VERSION 5.7 ;
  NOWIREEXTENSIONATPIN ON ;
  DIVIDERCHAR "/" ;
  BUSBITCHARS "[]" ;
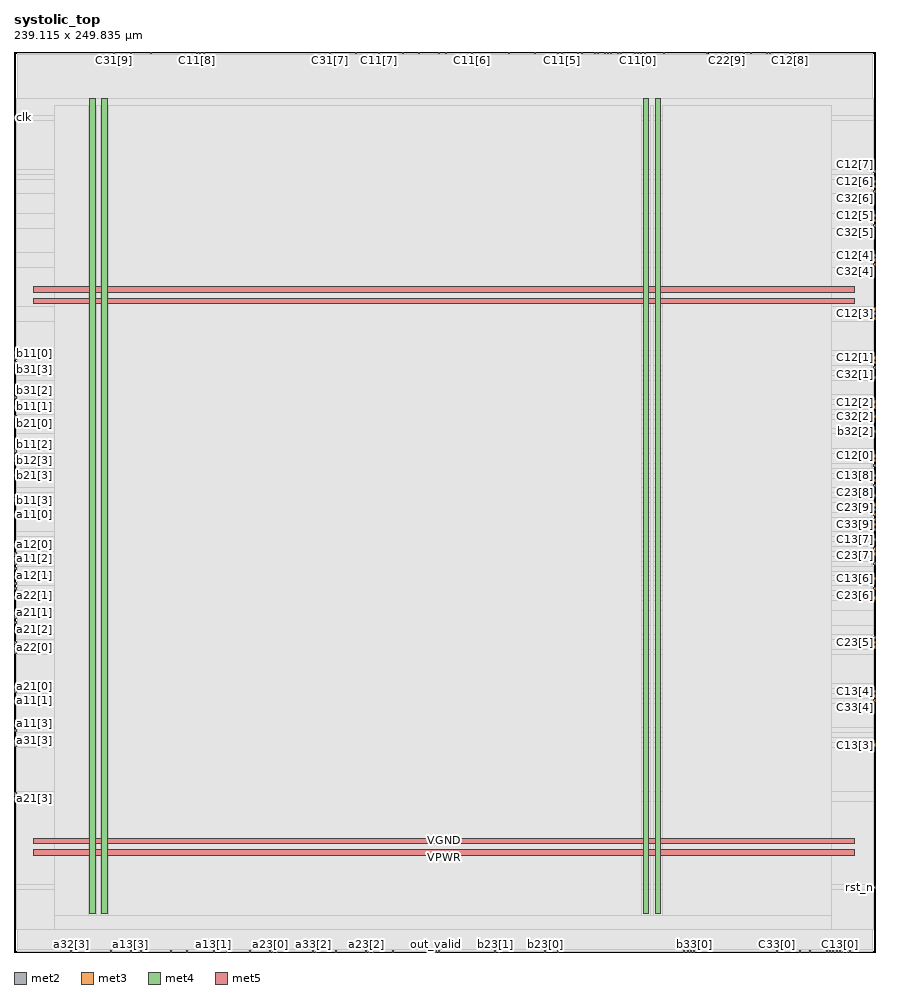
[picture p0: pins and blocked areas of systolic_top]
MACRO systolic_top
  CLASS BLOCK ;
  FOREIGN systolic_top ;
  ORIGIN 0.000 0.000 ;
  SIZE 239.115 BY 249.835 ;
  PIN C11[0]
    DIRECTION OUTPUT ;
    USE SIGNAL ;
    ANTENNADIFFAREA 0.702900 ;
    PORT
      LAYER met2 ;
        RECT 173.050 249.555 173.330 249.835 ;
    END
  END C11[0]
  PIN C11[1]
    DIRECTION OUTPUT ;
    USE SIGNAL ;
    ANTENNADIFFAREA 0.702900 ;
    PORT
      LAYER met2 ;
        RECT 165.690 249.555 165.970 249.835 ;
    END
  END C11[1]
  PIN C11[2]
    DIRECTION OUTPUT ;
    USE SIGNAL ;
    ANTENNADIFFAREA 0.702900 ;
    PORT
      LAYER met2 ;
        RECT 174.890 249.555 175.170 249.835 ;
    END
  END C11[2]
  PIN C11[3]
    DIRECTION OUTPUT ;
    USE SIGNAL ;
    ANTENNADIFFAREA 0.702900 ;
    PORT
      LAYER met2 ;
        RECT 180.410 249.555 180.690 249.835 ;
    END
  END C11[3]
  PIN C11[4]
    DIRECTION OUTPUT ;
    USE SIGNAL ;
    ANTENNADIFFAREA 0.702900 ;
    PORT
      LAYER met2 ;
        RECT 172.130 249.555 172.410 249.835 ;
    END
  END C11[4]
  PIN C11[5]
    DIRECTION OUTPUT ;
    USE SIGNAL ;
    ANTENNADIFFAREA 0.702900 ;
    PORT
      LAYER met2 ;
        RECT 151.890 249.555 152.170 249.835 ;
    END
  END C11[5]
  PIN C11[6]
    DIRECTION OUTPUT ;
    USE SIGNAL ;
    ANTENNADIFFAREA 0.702900 ;
    PORT
      LAYER met2 ;
        RECT 127.050 249.555 127.330 249.835 ;
    END
  END C11[6]
  PIN C11[7]
    DIRECTION OUTPUT ;
    USE SIGNAL ;
    ANTENNADIFFAREA 0.702900 ;
    PORT
      LAYER met2 ;
        RECT 101.290 249.555 101.570 249.835 ;
    END
  END C11[7]
  PIN C11[8]
    DIRECTION OUTPUT ;
    USE SIGNAL ;
    ANTENNADIFFAREA 0.702900 ;
    PORT
      LAYER met2 ;
        RECT 50.690 249.555 50.970 249.835 ;
    END
  END C11[8]
  PIN C11[9]
    DIRECTION OUTPUT ;
    USE SIGNAL ;
    ANTENNADIFFAREA 0.702900 ;
    PORT
      LAYER met2 ;
        RECT 37.810 249.555 38.090 249.835 ;
    END
  END C11[9]
  PIN C12[0]
    DIRECTION OUTPUT ;
    USE SIGNAL ;
    ANTENNADIFFAREA 0.702900 ;
    PORT
      LAYER met3 ;
        RECT 238.515 137.400 239.115 138.000 ;
    END
  END C12[0]
  PIN C12[1]
    DIRECTION OUTPUT ;
    USE SIGNAL ;
    ANTENNADIFFAREA 0.702900 ;
    PORT
      LAYER met3 ;
        RECT 238.515 164.600 239.115 165.200 ;
    END
  END C12[1]
  PIN C12[2]
    DIRECTION OUTPUT ;
    USE SIGNAL ;
    ANTENNADIFFAREA 0.702900 ;
    PORT
      LAYER met3 ;
        RECT 238.515 152.360 239.115 152.960 ;
    END
  END C12[2]
  PIN C12[3]
    DIRECTION OUTPUT ;
    USE SIGNAL ;
    ANTENNADIFFAREA 0.702900 ;
    PORT
      LAYER met3 ;
        RECT 238.515 176.840 239.115 177.440 ;
    END
  END C12[3]
  PIN C12[4]
    DIRECTION OUTPUT ;
    USE SIGNAL ;
    ANTENNADIFFAREA 0.702900 ;
    PORT
      LAYER met3 ;
        RECT 238.515 193.160 239.115 193.760 ;
    END
  END C12[4]
  PIN C12[5]
    DIRECTION OUTPUT ;
    USE SIGNAL ;
    ANTENNADIFFAREA 0.702900 ;
    PORT
      LAYER met3 ;
        RECT 238.515 204.040 239.115 204.640 ;
    END
  END C12[5]
  PIN C12[6]
    DIRECTION OUTPUT ;
    USE SIGNAL ;
    ANTENNADIFFAREA 0.702900 ;
    PORT
      LAYER met3 ;
        RECT 238.515 213.560 239.115 214.160 ;
    END
  END C12[6]
  PIN C12[7]
    DIRECTION OUTPUT ;
    USE SIGNAL ;
    ANTENNADIFFAREA 0.702900 ;
    PORT
      LAYER met3 ;
        RECT 238.515 216.280 239.115 216.880 ;
    END
  END C12[7]
  PIN C12[8]
    DIRECTION OUTPUT ;
    USE SIGNAL ;
    ANTENNADIFFAREA 0.702900 ;
    PORT
      LAYER met2 ;
        RECT 215.370 249.555 215.650 249.835 ;
    END
  END C12[8]
  PIN C12[9]
    DIRECTION OUTPUT ;
    USE SIGNAL ;
    ANTENNADIFFAREA 0.702900 ;
    PORT
      LAYER met2 ;
        RECT 204.330 249.555 204.610 249.835 ;
    END
  END C12[9]
  PIN C13[0]
    DIRECTION OUTPUT ;
    USE SIGNAL ;
    ANTENNADIFFAREA 0.702900 ;
    PORT
      LAYER met2 ;
        RECT 229.170 0.000 229.450 0.280 ;
    END
  END C13[0]
  PIN C13[1]
    DIRECTION OUTPUT ;
    USE SIGNAL ;
    ANTENNADIFFAREA 0.702900 ;
    PORT
      LAYER met2 ;
        RECT 231.930 0.000 232.210 0.280 ;
    END
  END C13[1]
  PIN C13[2]
    DIRECTION OUTPUT ;
    USE SIGNAL ;
    ANTENNADIFFAREA 0.702900 ;
    PORT
      LAYER met2 ;
        RECT 231.010 0.000 231.290 0.280 ;
    END
  END C13[2]
  PIN C13[3]
    DIRECTION OUTPUT ;
    USE SIGNAL ;
    ANTENNADIFFAREA 0.702900 ;
    PORT
      LAYER met3 ;
        RECT 238.515 57.160 239.115 57.760 ;
    END
  END C13[3]
  PIN C13[4]
    DIRECTION OUTPUT ;
    USE SIGNAL ;
    ANTENNADIFFAREA 0.702900 ;
    PORT
      LAYER met3 ;
        RECT 238.515 72.120 239.115 72.720 ;
    END
  END C13[4]
  PIN C13[5]
    DIRECTION OUTPUT ;
    USE SIGNAL ;
    ANTENNADIFFAREA 0.702900 ;
    PORT
      LAYER met3 ;
        RECT 238.515 87.080 239.115 87.680 ;
    END
  END C13[5]
  PIN C13[6]
    DIRECTION OUTPUT ;
    USE SIGNAL ;
    ANTENNADIFFAREA 0.702900 ;
    PORT
      LAYER met3 ;
        RECT 238.515 103.400 239.115 104.000 ;
    END
  END C13[6]
  PIN C13[7]
    DIRECTION OUTPUT ;
    USE SIGNAL ;
    ANTENNADIFFAREA 0.702900 ;
    PORT
      LAYER met3 ;
        RECT 238.515 114.280 239.115 114.880 ;
    END
  END C13[7]
  PIN C13[8]
    DIRECTION OUTPUT ;
    USE SIGNAL ;
    ANTENNADIFFAREA 0.702900 ;
    PORT
      LAYER met3 ;
        RECT 238.515 131.960 239.115 132.560 ;
    END
  END C13[8]
  PIN C13[9]
    DIRECTION OUTPUT ;
    USE SIGNAL ;
    ANTENNADIFFAREA 0.702900 ;
    PORT
      LAYER met3 ;
        RECT 238.515 123.800 239.115 124.400 ;
    END
  END C13[9]
  PIN C21[0]
    DIRECTION OUTPUT ;
    USE SIGNAL ;
    ANTENNADIFFAREA 0.702900 ;
    PORT
      LAYER met2 ;
        RECT 167.530 249.555 167.810 249.835 ;
    END
  END C21[0]
  PIN C21[1]
    DIRECTION OUTPUT ;
    USE SIGNAL ;
    ANTENNADIFFAREA 0.702900 ;
    PORT
      LAYER met2 ;
        RECT 157.410 249.555 157.690 249.835 ;
    END
  END C21[1]
  PIN C21[2]
    DIRECTION OUTPUT ;
    USE SIGNAL ;
    ANTENNADIFFAREA 0.702900 ;
    PORT
      LAYER met2 ;
        RECT 168.450 249.555 168.730 249.835 ;
    END
  END C21[2]
  PIN C21[3]
    DIRECTION OUTPUT ;
    USE SIGNAL ;
    ANTENNADIFFAREA 0.702900 ;
    PORT
      LAYER met2 ;
        RECT 173.970 249.555 174.250 249.835 ;
    END
  END C21[3]
  PIN C21[4]
    DIRECTION OUTPUT ;
    USE SIGNAL ;
    ANTENNADIFFAREA 0.702900 ;
    PORT
      LAYER met2 ;
        RECT 164.770 249.555 165.050 249.835 ;
    END
  END C21[4]
  PIN C21[5]
    DIRECTION OUTPUT ;
    USE SIGNAL ;
    ANTENNADIFFAREA 0.702900 ;
    PORT
      LAYER met2 ;
        RECT 144.530 249.555 144.810 249.835 ;
    END
  END C21[5]
  PIN C21[6]
    DIRECTION OUTPUT ;
    USE SIGNAL ;
    ANTENNADIFFAREA 0.702900 ;
    PORT
      LAYER met2 ;
        RECT 119.690 249.555 119.970 249.835 ;
    END
  END C21[6]
  PIN C21[7]
    DIRECTION OUTPUT ;
    USE SIGNAL ;
    ANTENNADIFFAREA 0.702900 ;
    PORT
      LAYER met2 ;
        RECT 94.850 249.555 95.130 249.835 ;
    END
  END C21[7]
  PIN C21[8]
    DIRECTION OUTPUT ;
    USE SIGNAL ;
    ANTENNADIFFAREA 0.702900 ;
    PORT
      LAYER met2 ;
        RECT 51.610 249.555 51.890 249.835 ;
    END
  END C21[8]
  PIN C21[9]
    DIRECTION OUTPUT ;
    USE SIGNAL ;
    ANTENNADIFFAREA 0.702900 ;
    PORT
      LAYER met2 ;
        RECT 32.290 249.555 32.570 249.835 ;
    END
  END C21[9]
  PIN C22[0]
    DIRECTION OUTPUT ;
    USE SIGNAL ;
    ANTENNADIFFAREA 0.702900 ;
    PORT
      LAYER met3 ;
        RECT 238.515 134.680 239.115 135.280 ;
    END
  END C22[0]
  PIN C22[1]
    DIRECTION OUTPUT ;
    USE SIGNAL ;
    ANTENNADIFFAREA 0.702900 ;
    PORT
      LAYER met3 ;
        RECT 238.515 163.240 239.115 163.840 ;
    END
  END C22[1]
  PIN C22[2]
    DIRECTION OUTPUT ;
    USE SIGNAL ;
    ANTENNADIFFAREA 0.702900 ;
    PORT
      LAYER met3 ;
        RECT 238.515 151.000 239.115 151.600 ;
    END
  END C22[2]
  PIN C22[3]
    DIRECTION OUTPUT ;
    USE SIGNAL ;
    ANTENNADIFFAREA 0.702900 ;
    PORT
      LAYER met3 ;
        RECT 238.515 175.480 239.115 176.080 ;
    END
  END C22[3]
  PIN C22[4]
    DIRECTION OUTPUT ;
    USE SIGNAL ;
    ANTENNADIFFAREA 0.702900 ;
    PORT
      LAYER met3 ;
        RECT 238.515 191.800 239.115 192.400 ;
    END
  END C22[4]
  PIN C22[5]
    DIRECTION OUTPUT ;
    USE SIGNAL ;
    ANTENNADIFFAREA 0.702900 ;
    PORT
      LAYER met3 ;
        RECT 238.515 202.680 239.115 203.280 ;
    END
  END C22[5]
  PIN C22[6]
    DIRECTION OUTPUT ;
    USE SIGNAL ;
    ANTENNADIFFAREA 0.702900 ;
    PORT
      LAYER met3 ;
        RECT 238.515 212.200 239.115 212.800 ;
    END
  END C22[6]
  PIN C22[7]
    DIRECTION OUTPUT ;
    USE SIGNAL ;
    ANTENNADIFFAREA 0.702900 ;
    PORT
      LAYER met2 ;
        RECT 216.290 249.555 216.570 249.835 ;
    END
  END C22[7]
  PIN C22[8]
    DIRECTION OUTPUT ;
    USE SIGNAL ;
    ANTENNADIFFAREA 0.702900 ;
    PORT
      LAYER met2 ;
        RECT 208.930 249.555 209.210 249.835 ;
    END
  END C22[8]
  PIN C22[9]
    DIRECTION OUTPUT ;
    USE SIGNAL ;
    ANTENNADIFFAREA 0.702900 ;
    PORT
      LAYER met2 ;
        RECT 197.890 249.555 198.170 249.835 ;
    END
  END C22[9]
  PIN C23[0]
    DIRECTION OUTPUT ;
    USE SIGNAL ;
    ANTENNADIFFAREA 0.702900 ;
    PORT
      LAYER met2 ;
        RECT 220.890 0.000 221.170 0.280 ;
    END
  END C23[0]
  PIN C23[1]
    DIRECTION OUTPUT ;
    USE SIGNAL ;
    ANTENNADIFFAREA 0.702900 ;
    PORT
      LAYER met2 ;
        RECT 225.490 0.000 225.770 0.280 ;
    END
  END C23[1]
  PIN C23[2]
    DIRECTION OUTPUT ;
    USE SIGNAL ;
    ANTENNADIFFAREA 0.702900 ;
    PORT
      LAYER met2 ;
        RECT 228.250 0.000 228.530 0.280 ;
    END
  END C23[2]
  PIN C23[3]
    DIRECTION OUTPUT ;
    USE SIGNAL ;
    ANTENNADIFFAREA 0.702900 ;
    PORT
      LAYER met2 ;
        RECT 230.090 0.000 230.370 0.280 ;
    END
  END C23[3]
  PIN C23[4]
    DIRECTION OUTPUT ;
    USE SIGNAL ;
    ANTENNADIFFAREA 0.702900 ;
    PORT
      LAYER met3 ;
        RECT 238.515 70.760 239.115 71.360 ;
    END
  END C23[4]
  PIN C23[5]
    DIRECTION OUTPUT ;
    USE SIGNAL ;
    ANTENNADIFFAREA 0.702900 ;
    PORT
      LAYER met3 ;
        RECT 238.515 85.720 239.115 86.320 ;
    END
  END C23[5]
  PIN C23[6]
    DIRECTION OUTPUT ;
    USE SIGNAL ;
    ANTENNADIFFAREA 0.702900 ;
    PORT
      LAYER met3 ;
        RECT 238.515 100.680 239.115 101.280 ;
    END
  END C23[6]
  PIN C23[7]
    DIRECTION OUTPUT ;
    USE SIGNAL ;
    ANTENNADIFFAREA 0.702900 ;
    PORT
      LAYER met3 ;
        RECT 238.515 111.560 239.115 112.160 ;
    END
  END C23[7]
  PIN C23[8]
    DIRECTION OUTPUT ;
    USE SIGNAL ;
    ANTENNADIFFAREA 0.702900 ;
    PORT
      LAYER met3 ;
        RECT 238.515 129.240 239.115 129.840 ;
    END
  END C23[8]
  PIN C23[9]
    DIRECTION OUTPUT ;
    USE SIGNAL ;
    ANTENNADIFFAREA 0.702900 ;
    PORT
      LAYER met3 ;
        RECT 238.515 121.080 239.115 121.680 ;
    END
  END C23[9]
  PIN C31[0]
    DIRECTION OUTPUT ;
    USE SIGNAL ;
    ANTENNADIFFAREA 0.702900 ;
    PORT
      LAYER met2 ;
        RECT 161.090 249.555 161.370 249.835 ;
    END
  END C31[0]
  PIN C31[1]
    DIRECTION OUTPUT ;
    USE SIGNAL ;
    ANTENNADIFFAREA 0.702900 ;
    PORT
      LAYER met2 ;
        RECT 150.970 249.555 151.250 249.835 ;
    END
  END C31[1]
  PIN C31[2]
    DIRECTION OUTPUT ;
    USE SIGNAL ;
    ANTENNADIFFAREA 0.702900 ;
    PORT
      LAYER met2 ;
        RECT 162.010 249.555 162.290 249.835 ;
    END
  END C31[2]
  PIN C31[3]
    DIRECTION OUTPUT ;
    USE SIGNAL ;
    ANTENNADIFFAREA 0.702900 ;
    PORT
      LAYER met2 ;
        RECT 163.850 249.555 164.130 249.835 ;
    END
  END C31[3]
  PIN C31[4]
    DIRECTION OUTPUT ;
    USE SIGNAL ;
    ANTENNADIFFAREA 0.702900 ;
    PORT
      LAYER met2 ;
        RECT 156.490 249.555 156.770 249.835 ;
    END
  END C31[4]
  PIN C31[5]
    DIRECTION OUTPUT ;
    USE SIGNAL ;
    ANTENNADIFFAREA 0.702900 ;
    PORT
      LAYER met2 ;
        RECT 137.170 249.555 137.450 249.835 ;
    END
  END C31[5]
  PIN C31[6]
    DIRECTION OUTPUT ;
    USE SIGNAL ;
    ANTENNADIFFAREA 0.702900 ;
    PORT
      LAYER met2 ;
        RECT 112.330 249.555 112.610 249.835 ;
    END
  END C31[6]
  PIN C31[7]
    DIRECTION OUTPUT ;
    USE SIGNAL ;
    ANTENNADIFFAREA 0.702900 ;
    PORT
      LAYER met2 ;
        RECT 87.490 249.555 87.770 249.835 ;
    END
  END C31[7]
  PIN C31[8]
    DIRECTION OUTPUT ;
    USE SIGNAL ;
    ANTENNADIFFAREA 0.702900 ;
    PORT
      LAYER met2 ;
        RECT 52.530 249.555 52.810 249.835 ;
    END
  END C31[8]
  PIN C31[9]
    DIRECTION OUTPUT ;
    USE SIGNAL ;
    ANTENNADIFFAREA 0.702900 ;
    PORT
      LAYER met2 ;
        RECT 27.690 249.555 27.970 249.835 ;
    END
  END C31[9]
  PIN C32[0]
    DIRECTION OUTPUT ;
    USE SIGNAL ;
    ANTENNADIFFAREA 0.702900 ;
    PORT
      LAYER met3 ;
        RECT 238.515 136.040 239.115 136.640 ;
    END
  END C32[0]
  PIN C32[1]
    DIRECTION OUTPUT ;
    USE SIGNAL ;
    ANTENNADIFFAREA 0.702900 ;
    PORT
      LAYER met3 ;
        RECT 238.515 161.880 239.115 162.480 ;
    END
  END C32[1]
  PIN C32[2]
    DIRECTION OUTPUT ;
    USE SIGNAL ;
    ANTENNADIFFAREA 0.702900 ;
    PORT
      LAYER met3 ;
        RECT 238.515 148.280 239.115 148.880 ;
    END
  END C32[2]
  PIN C32[3]
    DIRECTION OUTPUT ;
    USE SIGNAL ;
    ANTENNADIFFAREA 0.702900 ;
    PORT
      LAYER met3 ;
        RECT 238.515 178.200 239.115 178.800 ;
    END
  END C32[3]
  PIN C32[4]
    DIRECTION OUTPUT ;
    USE SIGNAL ;
    ANTENNADIFFAREA 0.702900 ;
    PORT
      LAYER met3 ;
        RECT 238.515 190.440 239.115 191.040 ;
    END
  END C32[4]
  PIN C32[5]
    DIRECTION OUTPUT ;
    USE SIGNAL ;
    ANTENNADIFFAREA 0.702900 ;
    PORT
      LAYER met3 ;
        RECT 238.515 201.320 239.115 201.920 ;
    END
  END C32[5]
  PIN C32[6]
    DIRECTION OUTPUT ;
    USE SIGNAL ;
    ANTENNADIFFAREA 0.702900 ;
    PORT
      LAYER met3 ;
        RECT 238.515 210.840 239.115 211.440 ;
    END
  END C32[6]
  PIN C32[7]
    DIRECTION OUTPUT ;
    USE SIGNAL ;
    ANTENNADIFFAREA 0.702900 ;
    PORT
      LAYER met2 ;
        RECT 209.850 249.555 210.130 249.835 ;
    END
  END C32[7]
  PIN C32[8]
    DIRECTION OUTPUT ;
    USE SIGNAL ;
    ANTENNADIFFAREA 0.702900 ;
    PORT
      LAYER met2 ;
        RECT 202.490 249.555 202.770 249.835 ;
    END
  END C32[8]
  PIN C32[9]
    DIRECTION OUTPUT ;
    USE SIGNAL ;
    ANTENNADIFFAREA 0.702900 ;
    PORT
      LAYER met2 ;
        RECT 192.370 249.555 192.650 249.835 ;
    END
  END C32[9]
  PIN C33[0]
    DIRECTION OUTPUT ;
    USE SIGNAL ;
    ANTENNADIFFAREA 0.702900 ;
    PORT
      LAYER met2 ;
        RECT 211.690 0.000 211.970 0.280 ;
    END
  END C33[0]
  PIN C33[1]
    DIRECTION OUTPUT ;
    USE SIGNAL ;
    ANTENNADIFFAREA 0.702900 ;
    PORT
      LAYER met2 ;
        RECT 218.130 0.000 218.410 0.280 ;
    END
  END C33[1]
  PIN C33[2]
    DIRECTION OUTPUT ;
    USE SIGNAL ;
    ANTENNADIFFAREA 0.702900 ;
    PORT
      LAYER met2 ;
        RECT 226.410 0.000 226.690 0.280 ;
    END
  END C33[2]
  PIN C33[3]
    DIRECTION OUTPUT ;
    USE SIGNAL ;
    ANTENNADIFFAREA 0.702900 ;
    PORT
      LAYER met2 ;
        RECT 227.330 0.000 227.610 0.280 ;
    END
  END C33[3]
  PIN C33[4]
    DIRECTION OUTPUT ;
    USE SIGNAL ;
    ANTENNADIFFAREA 0.702900 ;
    PORT
      LAYER met3 ;
        RECT 238.515 69.400 239.115 70.000 ;
    END
  END C33[4]
  PIN C33[5]
    DIRECTION OUTPUT ;
    USE SIGNAL ;
    ANTENNADIFFAREA 0.702900 ;
    PORT
      LAYER met3 ;
        RECT 238.515 84.360 239.115 84.960 ;
    END
  END C33[5]
  PIN C33[6]
    DIRECTION OUTPUT ;
    USE SIGNAL ;
    ANTENNADIFFAREA 0.702900 ;
    PORT
      LAYER met3 ;
        RECT 238.515 97.960 239.115 98.560 ;
    END
  END C33[6]
  PIN C33[7]
    DIRECTION OUTPUT ;
    USE SIGNAL ;
    ANTENNADIFFAREA 0.702900 ;
    PORT
      LAYER met3 ;
        RECT 238.515 110.200 239.115 110.800 ;
    END
  END C33[7]
  PIN C33[8]
    DIRECTION OUTPUT ;
    USE SIGNAL ;
    ANTENNADIFFAREA 0.702900 ;
    PORT
      LAYER met3 ;
        RECT 238.515 126.520 239.115 127.120 ;
    END
  END C33[8]
  PIN C33[9]
    DIRECTION OUTPUT ;
    USE SIGNAL ;
    ANTENNADIFFAREA 0.702900 ;
    PORT
      LAYER met3 ;
        RECT 238.515 118.360 239.115 118.960 ;
    END
  END C33[9]
  PIN VGND
    DIRECTION INOUT ;
    USE GROUND ;
    PORT
      LAYER met4 ;
        RECT 24.340 10.640 25.940 236.880 ;
    END
    PORT
      LAYER met4 ;
        RECT 177.940 10.640 179.540 236.880 ;
    END
    PORT
      LAYER met5 ;
        RECT 5.520 30.030 233.220 31.630 ;
    END
    PORT
      LAYER met5 ;
        RECT 5.520 183.210 233.220 184.810 ;
    END
  END VGND
  PIN VPWR
    DIRECTION INOUT ;
    USE POWER ;
    PORT
      LAYER met4 ;
        RECT 21.040 10.640 22.640 236.880 ;
    END
    PORT
      LAYER met4 ;
        RECT 174.640 10.640 176.240 236.880 ;
    END
    PORT
      LAYER met5 ;
        RECT 5.520 26.730 233.220 28.330 ;
    END
    PORT
      LAYER met5 ;
        RECT 5.520 179.910 233.220 181.510 ;
    END
  END VPWR
  PIN a11[0]
    DIRECTION INPUT ;
    USE SIGNAL ;
    ANTENNAGATEAREA 0.213000 ;
    PORT
      LAYER met3 ;
        RECT 0.000 121.080 0.600 121.680 ;
    END
  END a11[0]
  PIN a11[1]
    DIRECTION INPUT ;
    USE SIGNAL ;
    ANTENNAGATEAREA 0.213000 ;
    PORT
      LAYER met3 ;
        RECT 0.000 69.400 0.600 70.000 ;
    END
  END a11[1]
  PIN a11[2]
    DIRECTION INPUT ;
    USE SIGNAL ;
    ANTENNAGATEAREA 0.213000 ;
    PORT
      LAYER met3 ;
        RECT 0.000 108.840 0.600 109.440 ;
    END
  END a11[2]
  PIN a11[3]
    DIRECTION INPUT ;
    USE SIGNAL ;
    ANTENNAGATEAREA 0.213000 ;
    PORT
      LAYER met3 ;
        RECT 0.000 61.240 0.600 61.840 ;
    END
  END a11[3]
  PIN a12[0]
    DIRECTION INPUT ;
    USE SIGNAL ;
    ANTENNAGATEAREA 0.213000 ;
    PORT
      LAYER met3 ;
        RECT 0.000 112.920 0.600 113.520 ;
    END
  END a12[0]
  PIN a12[1]
    DIRECTION INPUT ;
    USE SIGNAL ;
    ANTENNAGATEAREA 0.213000 ;
    PORT
      LAYER met3 ;
        RECT 0.000 106.120 0.600 106.720 ;
    END
  END a12[1]
  PIN a12[2]
    DIRECTION INPUT ;
    USE SIGNAL ;
    ANTENNAGATEAREA 0.213000 ;
    PORT
      LAYER met3 ;
        RECT 0.000 110.200 0.600 110.800 ;
    END
  END a12[2]
  PIN a12[3]
    DIRECTION INPUT ;
    USE SIGNAL ;
    ANTENNAGATEAREA 0.213000 ;
    PORT
      LAYER met3 ;
        RECT 0.000 57.160 0.600 57.760 ;
    END
  END a12[3]
  PIN a13[0]
    DIRECTION INPUT ;
    USE SIGNAL ;
    ANTENNAGATEAREA 0.213000 ;
    PORT
      LAYER met2 ;
        RECT 71.850 0.000 72.130 0.280 ;
    END
  END a13[0]
  PIN a13[1]
    DIRECTION INPUT ;
    USE SIGNAL ;
    ANTENNAGATEAREA 0.213000 ;
    PORT
      LAYER met2 ;
        RECT 55.290 0.000 55.570 0.280 ;
    END
  END a13[1]
  PIN a13[2]
    DIRECTION INPUT ;
    USE SIGNAL ;
    ANTENNAGATEAREA 0.213000 ;
    PORT
      LAYER met2 ;
        RECT 72.770 0.000 73.050 0.280 ;
    END
  END a13[2]
  PIN a13[3]
    DIRECTION INPUT ;
    USE SIGNAL ;
    ANTENNAGATEAREA 0.213000 ;
    PORT
      LAYER met2 ;
        RECT 32.290 0.000 32.570 0.280 ;
    END
  END a13[3]
  PIN a21[0]
    DIRECTION INPUT ;
    USE SIGNAL ;
    ANTENNAGATEAREA 0.213000 ;
    PORT
      LAYER met3 ;
        RECT 0.000 73.480 0.600 74.080 ;
    END
  END a21[0]
  PIN a21[1]
    DIRECTION INPUT ;
    USE SIGNAL ;
    ANTENNAGATEAREA 0.213000 ;
    PORT
      LAYER met3 ;
        RECT 0.000 93.880 0.600 94.480 ;
    END
  END a21[1]
  PIN a21[2]
    DIRECTION INPUT ;
    USE SIGNAL ;
    ANTENNAGATEAREA 0.213000 ;
    PORT
      LAYER met3 ;
        RECT 0.000 91.160 0.600 91.760 ;
    END
  END a21[2]
  PIN a21[3]
    DIRECTION INPUT ;
    USE SIGNAL ;
    ANTENNAGATEAREA 0.213000 ;
    PORT
      LAYER met3 ;
        RECT 0.000 42.200 0.600 42.800 ;
    END
  END a21[3]
  PIN a22[0]
    DIRECTION INPUT ;
    USE SIGNAL ;
    ANTENNAGATEAREA 0.213000 ;
    PORT
      LAYER met3 ;
        RECT 0.000 84.360 0.600 84.960 ;
    END
  END a22[0]
  PIN a22[1]
    DIRECTION INPUT ;
    USE SIGNAL ;
    ANTENNAGATEAREA 0.213000 ;
    PORT
      LAYER met3 ;
        RECT 0.000 100.680 0.600 101.280 ;
    END
  END a22[1]
  PIN a22[2]
    DIRECTION INPUT ;
    USE SIGNAL ;
    ANTENNAGATEAREA 0.213000 ;
    PORT
      LAYER met3 ;
        RECT 0.000 102.040 0.600 102.640 ;
    END
  END a22[2]
  PIN a22[3]
    DIRECTION INPUT ;
    USE SIGNAL ;
    ANTENNAGATEAREA 0.213000 ;
    PORT
      LAYER met3 ;
        RECT 0.000 43.560 0.600 44.160 ;
    END
  END a22[3]
  PIN a23[0]
    DIRECTION INPUT ;
    USE SIGNAL ;
    ANTENNAGATEAREA 0.213000 ;
    PORT
      LAYER met2 ;
        RECT 70.930 0.000 71.210 0.280 ;
    END
  END a23[0]
  PIN a23[1]
    DIRECTION INPUT ;
    USE SIGNAL ;
    ANTENNAGATEAREA 0.213000 ;
    PORT
      LAYER met2 ;
        RECT 47.930 0.000 48.210 0.280 ;
    END
  END a23[1]
  PIN a23[2]
    DIRECTION INPUT ;
    USE SIGNAL ;
    ANTENNAGATEAREA 0.213000 ;
    PORT
      LAYER met2 ;
        RECT 97.610 0.000 97.890 0.280 ;
    END
  END a23[2]
  PIN a23[3]
    DIRECTION INPUT ;
    USE SIGNAL ;
    ANTENNAGATEAREA 0.213000 ;
    PORT
      LAYER met2 ;
        RECT 35.050 0.000 35.330 0.280 ;
    END
  END a23[3]
  PIN a31[0]
    DIRECTION INPUT ;
    USE SIGNAL ;
    ANTENNAGATEAREA 0.213000 ;
    PORT
      LAYER met2 ;
        RECT 65.410 0.000 65.690 0.280 ;
    END
  END a31[0]
  PIN a31[1]
    DIRECTION INPUT ;
    USE SIGNAL ;
    ANTENNAGATEAREA 0.213000 ;
    PORT
      LAYER met3 ;
        RECT 0.000 85.720 0.600 86.320 ;
    END
  END a31[1]
  PIN a31[2]
    DIRECTION INPUT ;
    USE SIGNAL ;
    ANTENNAGATEAREA 0.213000 ;
    PORT
      LAYER met3 ;
        RECT 0.000 83.000 0.600 83.600 ;
    END
  END a31[2]
  PIN a31[3]
    DIRECTION INPUT ;
    USE SIGNAL ;
    ANTENNAGATEAREA 0.213000 ;
    PORT
      LAYER met3 ;
        RECT 0.000 58.520 0.600 59.120 ;
    END
  END a31[3]
  PIN a32[0]
    DIRECTION INPUT ;
    USE SIGNAL ;
    ANTENNAGATEAREA 0.213000 ;
    PORT
      LAYER met3 ;
        RECT 0.000 72.120 0.600 72.720 ;
    END
  END a32[0]
  PIN a32[1]
    DIRECTION INPUT ;
    USE SIGNAL ;
    ANTENNAGATEAREA 0.213000 ;
    PORT
      LAYER met3 ;
        RECT 0.000 92.520 0.600 93.120 ;
    END
  END a32[1]
  PIN a32[2]
    DIRECTION INPUT ;
    USE SIGNAL ;
    ANTENNAGATEAREA 0.213000 ;
    PORT
      LAYER met3 ;
        RECT 0.000 97.960 0.600 98.560 ;
    END
  END a32[2]
  PIN a32[3]
    DIRECTION INPUT ;
    USE SIGNAL ;
    ANTENNAGATEAREA 0.213000 ;
    PORT
      LAYER met2 ;
        RECT 15.730 0.000 16.010 0.280 ;
    END
  END a32[3]
  PIN a33[0]
    DIRECTION INPUT ;
    USE SIGNAL ;
    ANTENNAGATEAREA 0.213000 ;
    PORT
      LAYER met2 ;
        RECT 58.970 0.000 59.250 0.280 ;
    END
  END a33[0]
  PIN a33[1]
    DIRECTION INPUT ;
    USE SIGNAL ;
    ANTENNAGATEAREA 0.213000 ;
    PORT
      LAYER met2 ;
        RECT 43.330 0.000 43.610 0.280 ;
    END
  END a33[1]
  PIN a33[2]
    DIRECTION INPUT ;
    USE SIGNAL ;
    ANTENNAGATEAREA 0.213000 ;
    PORT
      LAYER met2 ;
        RECT 82.890 0.000 83.170 0.280 ;
    END
  END a33[2]
  PIN a33[3]
    DIRECTION INPUT ;
    USE SIGNAL ;
    ANTENNAGATEAREA 0.213000 ;
    PORT
      LAYER met2 ;
        RECT 26.770 0.000 27.050 0.280 ;
    END
  END a33[3]
  PIN b11[0]
    DIRECTION INPUT ;
    USE SIGNAL ;
    ANTENNAGATEAREA 0.213000 ;
    PORT
      LAYER met3 ;
        RECT 0.000 165.960 0.600 166.560 ;
    END
  END b11[0]
  PIN b11[1]
    DIRECTION INPUT ;
    USE SIGNAL ;
    ANTENNAGATEAREA 0.213000 ;
    PORT
      LAYER met3 ;
        RECT 0.000 151.000 0.600 151.600 ;
    END
  END b11[1]
  PIN b11[2]
    DIRECTION INPUT ;
    USE SIGNAL ;
    ANTENNAGATEAREA 0.213000 ;
    PORT
      LAYER met3 ;
        RECT 0.000 138.760 0.600 139.360 ;
    END
  END b11[2]
  PIN b11[3]
    DIRECTION INPUT ;
    USE SIGNAL ;
    ANTENNAGATEAREA 0.213000 ;
    PORT
      LAYER met3 ;
        RECT 0.000 125.160 0.600 125.760 ;
    END
  END b11[3]
  PIN b12[0]
    DIRECTION INPUT ;
    USE SIGNAL ;
    ANTENNAGATEAREA 0.213000 ;
    PORT
      LAYER met2 ;
        RECT 98.530 0.000 98.810 0.280 ;
    END
  END b12[0]
  PIN b12[1]
    DIRECTION INPUT ;
    USE SIGNAL ;
    ANTENNAGATEAREA 0.213000 ;
    PORT
      LAYER met3 ;
        RECT 0.000 107.480 0.600 108.080 ;
    END
  END b12[1]
  PIN b12[2]
    DIRECTION INPUT ;
    USE SIGNAL ;
    ANTENNAGATEAREA 0.213000 ;
    PORT
      LAYER met2 ;
        RECT 89.330 0.000 89.610 0.280 ;
    END
  END b12[2]
  PIN b12[3]
    DIRECTION INPUT ;
    USE SIGNAL ;
    ANTENNAGATEAREA 0.213000 ;
    PORT
      LAYER met3 ;
        RECT 0.000 136.040 0.600 136.640 ;
    END
  END b12[3]
  PIN b13[0]
    DIRECTION INPUT ;
    USE SIGNAL ;
    ANTENNAGATEAREA 0.213000 ;
    PORT
      LAYER met2 ;
        RECT 117.850 0.000 118.130 0.280 ;
    END
  END b13[0]
  PIN b13[1]
    DIRECTION INPUT ;
    USE SIGNAL ;
    ANTENNAGATEAREA 0.213000 ;
    PORT
      LAYER met2 ;
        RECT 99.450 0.000 99.730 0.280 ;
    END
  END b13[1]
  PIN b13[2]
    DIRECTION INPUT ;
    USE SIGNAL ;
    ANTENNAGATEAREA 0.213000 ;
    PORT
      LAYER met2 ;
        RECT 104.970 0.000 105.250 0.280 ;
    END
  END b13[2]
  PIN b13[3]
    DIRECTION INPUT ;
    USE SIGNAL ;
    ANTENNAGATEAREA 0.213000 ;
    PORT
      LAYER met2 ;
        RECT 115.090 0.000 115.370 0.280 ;
    END
  END b13[3]
  PIN b21[0]
    DIRECTION INPUT ;
    USE SIGNAL ;
    ANTENNAGATEAREA 0.213000 ;
    PORT
      LAYER met3 ;
        RECT 0.000 148.280 0.600 148.880 ;
    END
  END b21[0]
  PIN b21[1]
    DIRECTION INPUT ;
    USE SIGNAL ;
    ANTENNAGATEAREA 0.213000 ;
    PORT
      LAYER met3 ;
        RECT 0.000 126.520 0.600 127.120 ;
    END
  END b21[1]
  PIN b21[2]
    DIRECTION INPUT ;
    USE SIGNAL ;
    ANTENNAGATEAREA 0.213000 ;
    PORT
      LAYER met3 ;
        RECT 0.000 137.400 0.600 138.000 ;
    END
  END b21[2]
  PIN b21[3]
    DIRECTION INPUT ;
    USE SIGNAL ;
    ANTENNAGATEAREA 0.213000 ;
    PORT
      LAYER met3 ;
        RECT 0.000 131.960 0.600 132.560 ;
    END
  END b21[3]
  PIN b22[0]
    DIRECTION INPUT ;
    USE SIGNAL ;
    ANTENNAGATEAREA 0.213000 ;
    PORT
      LAYER met3 ;
        RECT 238.515 107.480 239.115 108.080 ;
    END
  END b22[0]
  PIN b22[1]
    DIRECTION INPUT ;
    USE SIGNAL ;
    ANTENNAGATEAREA 0.213000 ;
    PORT
      LAYER met3 ;
        RECT 238.515 119.720 239.115 120.320 ;
    END
  END b22[1]
  PIN b22[2]
    DIRECTION INPUT ;
    USE SIGNAL ;
    ANTENNAGATEAREA 0.213000 ;
    PORT
      LAYER met3 ;
        RECT 238.515 122.440 239.115 123.040 ;
    END
  END b22[2]
  PIN b22[3]
    DIRECTION INPUT ;
    USE SIGNAL ;
    ANTENNAGATEAREA 0.213000 ;
    PORT
      LAYER met2 ;
        RECT 117.850 249.555 118.130 249.835 ;
    END
  END b22[3]
  PIN b23[0]
    DIRECTION INPUT ;
    USE SIGNAL ;
    ANTENNAGATEAREA 0.213000 ;
    PORT
      LAYER met2 ;
        RECT 147.290 0.000 147.570 0.280 ;
    END
  END b23[0]
  PIN b23[1]
    DIRECTION INPUT ;
    USE SIGNAL ;
    ANTENNAGATEAREA 0.213000 ;
    PORT
      LAYER met2 ;
        RECT 133.490 0.000 133.770 0.280 ;
    END
  END b23[1]
  PIN b23[2]
    DIRECTION INPUT ;
    USE SIGNAL ;
    ANTENNAGATEAREA 0.213000 ;
    PORT
      LAYER met2 ;
        RECT 150.970 0.000 151.250 0.280 ;
    END
  END b23[2]
  PIN b23[3]
    DIRECTION INPUT ;
    USE SIGNAL ;
    ANTENNAGATEAREA 0.213000 ;
    PORT
      LAYER met2 ;
        RECT 134.410 0.000 134.690 0.280 ;
    END
  END b23[3]
  PIN b31[0]
    DIRECTION INPUT ;
    USE SIGNAL ;
    ANTENNAGATEAREA 0.213000 ;
    PORT
      LAYER met2 ;
        RECT 107.730 249.555 108.010 249.835 ;
    END
  END b31[0]
  PIN b31[1]
    DIRECTION INPUT ;
    USE SIGNAL ;
    ANTENNAGATEAREA 0.213000 ;
    PORT
      LAYER met3 ;
        RECT 0.000 164.600 0.600 165.200 ;
    END
  END b31[1]
  PIN b31[2]
    DIRECTION INPUT ;
    USE SIGNAL ;
    ANTENNAGATEAREA 0.213000 ;
    PORT
      LAYER met3 ;
        RECT 0.000 153.720 0.600 154.320 ;
    END
  END b31[2]
  PIN b31[3]
    DIRECTION INPUT ;
    USE SIGNAL ;
    ANTENNAGATEAREA 0.213000 ;
    PORT
      LAYER met3 ;
        RECT 0.000 163.240 0.600 163.840 ;
    END
  END b31[3]
  PIN b32[0]
    DIRECTION INPUT ;
    USE SIGNAL ;
    ANTENNAGATEAREA 0.213000 ;
    PORT
      LAYER met3 ;
        RECT 238.515 130.600 239.115 131.200 ;
    END
  END b32[0]
  PIN b32[1]
    DIRECTION INPUT ;
    USE SIGNAL ;
    ANTENNAGATEAREA 0.213000 ;
    PORT
      LAYER met3 ;
        RECT 238.515 117.000 239.115 117.600 ;
    END
  END b32[1]
  PIN b32[2]
    DIRECTION INPUT ;
    USE SIGNAL ;
    ANTENNAGATEAREA 0.213000 ;
    PORT
      LAYER met3 ;
        RECT 238.515 144.200 239.115 144.800 ;
    END
  END b32[2]
  PIN b32[3]
    DIRECTION INPUT ;
    USE SIGNAL ;
    ANTENNAGATEAREA 0.213000 ;
    PORT
      LAYER met3 ;
        RECT 238.515 159.160 239.115 159.760 ;
    END
  END b32[3]
  PIN b33[0]
    DIRECTION INPUT ;
    USE SIGNAL ;
    ANTENNAGATEAREA 0.213000 ;
    PORT
      LAYER met2 ;
        RECT 188.690 0.000 188.970 0.280 ;
    END
  END b33[0]
  PIN b33[1]
    DIRECTION INPUT ;
    USE SIGNAL ;
    ANTENNAGATEAREA 0.213000 ;
    PORT
      LAYER met2 ;
        RECT 185.930 0.000 186.210 0.280 ;
    END
  END b33[1]
  PIN b33[2]
    DIRECTION INPUT ;
    USE SIGNAL ;
    ANTENNAGATEAREA 0.213000 ;
    PORT
      LAYER met2 ;
        RECT 187.770 0.000 188.050 0.280 ;
    END
  END b33[2]
  PIN b33[3]
    DIRECTION INPUT ;
    USE SIGNAL ;
    ANTENNAGATEAREA 0.213000 ;
    PORT
      LAYER met2 ;
        RECT 186.850 0.000 187.130 0.280 ;
    END
  END b33[3]
  PIN clk
    DIRECTION INPUT ;
    USE SIGNAL ;
    ANTENNAGATEAREA 0.852000 ;
    PORT
      LAYER met3 ;
        RECT 0.000 231.240 0.600 231.840 ;
    END
  END clk
  PIN in_valid
    DIRECTION INPUT ;
    USE SIGNAL ;
    ANTENNAGATEAREA 0.213000 ;
    PORT
      LAYER met2 ;
        RECT 83.810 0.000 84.090 0.280 ;
    END
  END in_valid
  PIN out_valid
    DIRECTION OUTPUT ;
    USE SIGNAL ;
    ANTENNADIFFAREA 0.702900 ;
    PORT
      LAYER met2 ;
        RECT 116.930 0.000 117.210 0.280 ;
    END
  END out_valid
  PIN rst_n
    DIRECTION INPUT ;
    USE SIGNAL ;
    ANTENNAGATEAREA 0.213000 ;
    PORT
      LAYER met3 ;
        RECT 238.515 17.720 239.115 18.320 ;
    END
  END rst_n
  OBS
      LAYER nwell ;
        RECT 5.330 10.795 233.410 236.830 ;
      LAYER li1 ;
        RECT 5.520 10.795 233.220 236.725 ;
      LAYER met1 ;
        RECT 0.990 4.120 238.210 244.080 ;
      LAYER met2 ;
        RECT 1.010 249.275 27.410 249.555 ;
        RECT 28.250 249.275 32.010 249.555 ;
        RECT 32.850 249.275 37.530 249.555 ;
        RECT 38.370 249.275 50.410 249.555 ;
        RECT 51.250 249.275 51.330 249.555 ;
        RECT 52.170 249.275 52.250 249.555 ;
        RECT 53.090 249.275 87.210 249.555 ;
        RECT 88.050 249.275 94.570 249.555 ;
        RECT 95.410 249.275 101.010 249.555 ;
        RECT 101.850 249.275 107.450 249.555 ;
        RECT 108.290 249.275 112.050 249.555 ;
        RECT 112.890 249.275 117.570 249.555 ;
        RECT 118.410 249.275 119.410 249.555 ;
        RECT 120.250 249.275 126.770 249.555 ;
        RECT 127.610 249.275 136.890 249.555 ;
        RECT 137.730 249.275 144.250 249.555 ;
        RECT 145.090 249.275 150.690 249.555 ;
        RECT 151.530 249.275 151.610 249.555 ;
        RECT 152.450 249.275 156.210 249.555 ;
        RECT 157.050 249.275 157.130 249.555 ;
        RECT 157.970 249.275 160.810 249.555 ;
        RECT 161.650 249.275 161.730 249.555 ;
        RECT 162.570 249.275 163.570 249.555 ;
        RECT 164.410 249.275 164.490 249.555 ;
        RECT 165.330 249.275 165.410 249.555 ;
        RECT 166.250 249.275 167.250 249.555 ;
        RECT 168.090 249.275 168.170 249.555 ;
        RECT 169.010 249.275 171.850 249.555 ;
        RECT 172.690 249.275 172.770 249.555 ;
        RECT 173.610 249.275 173.690 249.555 ;
        RECT 174.530 249.275 174.610 249.555 ;
        RECT 175.450 249.275 180.130 249.555 ;
        RECT 180.970 249.275 192.090 249.555 ;
        RECT 192.930 249.275 197.610 249.555 ;
        RECT 198.450 249.275 202.210 249.555 ;
        RECT 203.050 249.275 204.050 249.555 ;
        RECT 204.890 249.275 208.650 249.555 ;
        RECT 209.490 249.275 209.570 249.555 ;
        RECT 210.410 249.275 215.090 249.555 ;
        RECT 215.930 249.275 216.010 249.555 ;
        RECT 216.850 249.275 238.190 249.555 ;
        RECT 1.010 0.560 238.190 249.275 ;
        RECT 1.010 0.070 15.450 0.560 ;
        RECT 16.290 0.070 26.490 0.560 ;
        RECT 27.330 0.070 32.010 0.560 ;
        RECT 32.850 0.070 34.770 0.560 ;
        RECT 35.610 0.070 43.050 0.560 ;
        RECT 43.890 0.070 47.650 0.560 ;
        RECT 48.490 0.070 55.010 0.560 ;
        RECT 55.850 0.070 58.690 0.560 ;
        RECT 59.530 0.070 65.130 0.560 ;
        RECT 65.970 0.070 70.650 0.560 ;
        RECT 71.490 0.070 71.570 0.560 ;
        RECT 72.410 0.070 72.490 0.560 ;
        RECT 73.330 0.070 82.610 0.560 ;
        RECT 83.450 0.070 83.530 0.560 ;
        RECT 84.370 0.070 89.050 0.560 ;
        RECT 89.890 0.070 97.330 0.560 ;
        RECT 98.170 0.070 98.250 0.560 ;
        RECT 99.090 0.070 99.170 0.560 ;
        RECT 100.010 0.070 104.690 0.560 ;
        RECT 105.530 0.070 114.810 0.560 ;
        RECT 115.650 0.070 116.650 0.560 ;
        RECT 117.490 0.070 117.570 0.560 ;
        RECT 118.410 0.070 133.210 0.560 ;
        RECT 134.050 0.070 134.130 0.560 ;
        RECT 134.970 0.070 147.010 0.560 ;
        RECT 147.850 0.070 150.690 0.560 ;
        RECT 151.530 0.070 185.650 0.560 ;
        RECT 186.490 0.070 186.570 0.560 ;
        RECT 187.410 0.070 187.490 0.560 ;
        RECT 188.330 0.070 188.410 0.560 ;
        RECT 189.250 0.070 211.410 0.560 ;
        RECT 212.250 0.070 217.850 0.560 ;
        RECT 218.690 0.070 220.610 0.560 ;
        RECT 221.450 0.070 225.210 0.560 ;
        RECT 226.050 0.070 226.130 0.560 ;
        RECT 226.970 0.070 227.050 0.560 ;
        RECT 227.890 0.070 227.970 0.560 ;
        RECT 228.810 0.070 228.890 0.560 ;
        RECT 229.730 0.070 229.810 0.560 ;
        RECT 230.650 0.070 230.730 0.560 ;
        RECT 231.570 0.070 231.650 0.560 ;
        RECT 232.490 0.070 238.190 0.560 ;
      LAYER met3 ;
        RECT 0.600 232.240 238.515 236.805 ;
        RECT 1.000 230.840 238.515 232.240 ;
        RECT 0.600 217.280 238.515 230.840 ;
        RECT 0.600 215.880 238.115 217.280 ;
        RECT 0.600 214.560 238.515 215.880 ;
        RECT 0.600 210.440 238.115 214.560 ;
        RECT 0.600 205.040 238.515 210.440 ;
        RECT 0.600 200.920 238.115 205.040 ;
        RECT 0.600 194.160 238.515 200.920 ;
        RECT 0.600 190.040 238.115 194.160 ;
        RECT 0.600 179.200 238.515 190.040 ;
        RECT 0.600 175.080 238.115 179.200 ;
        RECT 0.600 166.960 238.515 175.080 ;
        RECT 1.000 165.600 238.515 166.960 ;
        RECT 1.000 162.840 238.115 165.600 ;
        RECT 0.600 161.480 238.115 162.840 ;
        RECT 0.600 160.160 238.515 161.480 ;
        RECT 0.600 158.760 238.115 160.160 ;
        RECT 0.600 154.720 238.515 158.760 ;
        RECT 1.000 153.360 238.515 154.720 ;
        RECT 1.000 153.320 238.115 153.360 ;
        RECT 0.600 152.000 238.115 153.320 ;
        RECT 1.000 150.600 238.115 152.000 ;
        RECT 0.600 149.280 238.515 150.600 ;
        RECT 1.000 147.880 238.115 149.280 ;
        RECT 0.600 145.200 238.515 147.880 ;
        RECT 0.600 143.800 238.115 145.200 ;
        RECT 0.600 139.760 238.515 143.800 ;
        RECT 1.000 138.400 238.515 139.760 ;
        RECT 1.000 135.640 238.115 138.400 ;
        RECT 0.600 134.280 238.115 135.640 ;
        RECT 0.600 132.960 238.515 134.280 ;
        RECT 1.000 131.560 238.115 132.960 ;
        RECT 0.600 128.840 238.115 131.560 ;
        RECT 0.600 127.520 238.515 128.840 ;
        RECT 1.000 126.120 238.115 127.520 ;
        RECT 1.000 124.800 238.515 126.120 ;
        RECT 1.000 124.760 238.115 124.800 ;
        RECT 0.600 122.080 238.115 124.760 ;
        RECT 1.000 120.680 238.115 122.080 ;
        RECT 0.600 116.600 238.115 120.680 ;
        RECT 0.600 115.280 238.515 116.600 ;
        RECT 0.600 113.920 238.115 115.280 ;
        RECT 1.000 113.880 238.115 113.920 ;
        RECT 1.000 112.560 238.515 113.880 ;
        RECT 1.000 112.520 238.115 112.560 ;
        RECT 0.600 111.200 238.115 112.520 ;
        RECT 1.000 109.800 238.115 111.200 ;
        RECT 1.000 108.480 238.515 109.800 ;
        RECT 1.000 107.080 238.115 108.480 ;
        RECT 1.000 105.720 238.515 107.080 ;
        RECT 0.600 104.400 238.515 105.720 ;
        RECT 0.600 103.040 238.115 104.400 ;
        RECT 1.000 103.000 238.115 103.040 ;
        RECT 1.000 101.680 238.515 103.000 ;
        RECT 1.000 100.280 238.115 101.680 ;
        RECT 0.600 98.960 238.515 100.280 ;
        RECT 1.000 97.560 238.115 98.960 ;
        RECT 0.600 94.880 238.515 97.560 ;
        RECT 1.000 90.760 238.515 94.880 ;
        RECT 0.600 88.080 238.515 90.760 ;
        RECT 0.600 86.720 238.115 88.080 ;
        RECT 1.000 83.960 238.115 86.720 ;
        RECT 1.000 82.600 238.515 83.960 ;
        RECT 0.600 74.480 238.515 82.600 ;
        RECT 1.000 73.120 238.515 74.480 ;
        RECT 1.000 71.720 238.115 73.120 ;
        RECT 0.600 70.400 238.115 71.720 ;
        RECT 1.000 69.000 238.115 70.400 ;
        RECT 0.600 62.240 238.515 69.000 ;
        RECT 1.000 60.840 238.515 62.240 ;
        RECT 0.600 59.520 238.515 60.840 ;
        RECT 1.000 58.160 238.515 59.520 ;
        RECT 1.000 56.760 238.115 58.160 ;
        RECT 0.600 44.560 238.515 56.760 ;
        RECT 1.000 41.800 238.515 44.560 ;
        RECT 0.600 18.720 238.515 41.800 ;
        RECT 0.600 17.320 238.115 18.720 ;
        RECT 0.600 6.295 238.515 17.320 ;
      LAYER met4 ;
        RECT 11.335 10.240 20.640 235.105 ;
        RECT 23.040 10.240 23.940 235.105 ;
        RECT 26.340 10.240 174.240 235.105 ;
        RECT 176.640 10.240 177.540 235.105 ;
        RECT 179.940 10.240 226.945 235.105 ;
        RECT 11.335 6.295 226.945 10.240 ;
  END
END systolic_top
END LIBRARY

